VERSION 5.7 ;
  NOWIREEXTENSIONATPIN ON ;
  DIVIDERCHAR "/" ;
  BUSBITCHARS "[]" ;
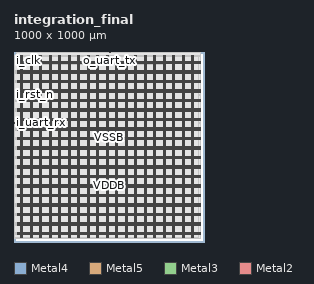
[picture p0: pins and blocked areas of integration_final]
MACRO integration_final
  CLASS BLOCK ;
  FOREIGN integration_final ;
  ORIGIN 0.000 0.000 ;
  SIZE 1000.000 BY 1000.000 ;
  PIN VDDB
    DIRECTION INOUT ;
    USE POWER ;
    PORT
      LAYER Metal4 ;
        RECT 42.080 23.220 43.680 980.300 ;
    END
    PORT
      LAYER Metal4 ;
        RECT 92.080 23.220 93.680 980.300 ;
    END
    PORT
      LAYER Metal4 ;
        RECT 142.080 23.220 143.680 980.300 ;
    END
    PORT
      LAYER Metal4 ;
        RECT 192.080 23.220 193.680 980.300 ;
    END
    PORT
      LAYER Metal4 ;
        RECT 242.080 23.220 243.680 980.300 ;
    END
    PORT
      LAYER Metal4 ;
        RECT 292.080 23.220 293.680 980.300 ;
    END
    PORT
      LAYER Metal4 ;
        RECT 342.080 23.220 343.680 980.300 ;
    END
    PORT
      LAYER Metal4 ;
        RECT 392.080 23.220 393.680 980.300 ;
    END
    PORT
      LAYER Metal4 ;
        RECT 442.080 23.220 443.680 980.300 ;
    END
    PORT
      LAYER Metal4 ;
        RECT 492.080 23.220 493.680 980.300 ;
    END
    PORT
      LAYER Metal4 ;
        RECT 542.080 23.220 543.680 980.300 ;
    END
    PORT
      LAYER Metal4 ;
        RECT 592.080 23.220 593.680 980.300 ;
    END
    PORT
      LAYER Metal4 ;
        RECT 642.080 23.220 643.680 980.300 ;
    END
    PORT
      LAYER Metal4 ;
        RECT 692.080 23.220 693.680 980.300 ;
    END
    PORT
      LAYER Metal4 ;
        RECT 742.080 23.220 743.680 980.300 ;
    END
    PORT
      LAYER Metal4 ;
        RECT 792.080 23.220 793.680 980.300 ;
    END
    PORT
      LAYER Metal4 ;
        RECT 842.080 23.220 843.680 980.300 ;
    END
    PORT
      LAYER Metal4 ;
        RECT 892.080 23.220 893.680 980.300 ;
    END
    PORT
      LAYER Metal4 ;
        RECT 942.080 23.220 943.680 980.300 ;
    END
    PORT
      LAYER Metal5 ;
        RECT 20.160 45.770 980.000 47.370 ;
    END
    PORT
      LAYER Metal5 ;
        RECT 20.160 95.770 980.000 97.370 ;
    END
    PORT
      LAYER Metal5 ;
        RECT 20.160 145.770 980.000 147.370 ;
    END
    PORT
      LAYER Metal5 ;
        RECT 20.160 195.770 980.000 197.370 ;
    END
    PORT
      LAYER Metal5 ;
        RECT 20.160 245.770 980.000 247.370 ;
    END
    PORT
      LAYER Metal5 ;
        RECT 20.160 295.770 980.000 297.370 ;
    END
    PORT
      LAYER Metal5 ;
        RECT 20.160 345.770 980.000 347.370 ;
    END
    PORT
      LAYER Metal5 ;
        RECT 20.160 395.770 980.000 397.370 ;
    END
    PORT
      LAYER Metal5 ;
        RECT 20.160 445.770 980.000 447.370 ;
    END
    PORT
      LAYER Metal5 ;
        RECT 20.160 495.770 980.000 497.370 ;
    END
    PORT
      LAYER Metal5 ;
        RECT 20.160 545.770 980.000 547.370 ;
    END
    PORT
      LAYER Metal5 ;
        RECT 20.160 595.770 980.000 597.370 ;
    END
    PORT
      LAYER Metal5 ;
        RECT 20.160 645.770 980.000 647.370 ;
    END
    PORT
      LAYER Metal5 ;
        RECT 20.160 695.770 980.000 697.370 ;
    END
    PORT
      LAYER Metal5 ;
        RECT 20.160 745.770 980.000 747.370 ;
    END
    PORT
      LAYER Metal5 ;
        RECT 20.160 795.770 980.000 797.370 ;
    END
    PORT
      LAYER Metal5 ;
        RECT 20.160 845.770 980.000 847.370 ;
    END
    PORT
      LAYER Metal5 ;
        RECT 20.160 895.770 980.000 897.370 ;
    END
    PORT
      LAYER Metal5 ;
        RECT 20.160 945.770 980.000 947.370 ;
    END
  END VDDB
  PIN VDDD
    DIRECTION INOUT ;
    USE POWER ;
    PORT
      LAYER Metal4 ;
        RECT 35.680 23.220 37.280 980.300 ;
    END
    PORT
      LAYER Metal4 ;
        RECT 85.680 23.220 87.280 980.300 ;
    END
    PORT
      LAYER Metal4 ;
        RECT 135.680 23.220 137.280 980.300 ;
    END
    PORT
      LAYER Metal4 ;
        RECT 185.680 23.220 187.280 980.300 ;
    END
    PORT
      LAYER Metal4 ;
        RECT 235.680 23.220 237.280 980.300 ;
    END
    PORT
      LAYER Metal4 ;
        RECT 285.680 23.220 287.280 980.300 ;
    END
    PORT
      LAYER Metal4 ;
        RECT 335.680 23.220 337.280 980.300 ;
    END
    PORT
      LAYER Metal4 ;
        RECT 385.680 23.220 387.280 980.300 ;
    END
    PORT
      LAYER Metal4 ;
        RECT 435.680 23.220 437.280 980.300 ;
    END
    PORT
      LAYER Metal4 ;
        RECT 485.680 23.220 487.280 980.300 ;
    END
    PORT
      LAYER Metal4 ;
        RECT 535.680 23.220 537.280 980.300 ;
    END
    PORT
      LAYER Metal4 ;
        RECT 585.680 23.220 587.280 980.300 ;
    END
    PORT
      LAYER Metal4 ;
        RECT 635.680 23.220 637.280 980.300 ;
    END
    PORT
      LAYER Metal4 ;
        RECT 685.680 23.220 687.280 980.300 ;
    END
    PORT
      LAYER Metal4 ;
        RECT 735.680 23.220 737.280 980.300 ;
    END
    PORT
      LAYER Metal4 ;
        RECT 785.680 23.220 787.280 980.300 ;
    END
    PORT
      LAYER Metal4 ;
        RECT 835.680 23.220 837.280 980.300 ;
    END
    PORT
      LAYER Metal4 ;
        RECT 885.680 23.220 887.280 980.300 ;
    END
    PORT
      LAYER Metal4 ;
        RECT 935.680 23.220 937.280 980.300 ;
    END
    PORT
      LAYER Metal5 ;
        RECT 20.160 39.370 980.000 40.970 ;
    END
    PORT
      LAYER Metal5 ;
        RECT 20.160 89.370 980.000 90.970 ;
    END
    PORT
      LAYER Metal5 ;
        RECT 20.160 139.370 980.000 140.970 ;
    END
    PORT
      LAYER Metal5 ;
        RECT 20.160 189.370 980.000 190.970 ;
    END
    PORT
      LAYER Metal5 ;
        RECT 20.160 239.370 980.000 240.970 ;
    END
    PORT
      LAYER Metal5 ;
        RECT 20.160 289.370 980.000 290.970 ;
    END
    PORT
      LAYER Metal5 ;
        RECT 20.160 339.370 980.000 340.970 ;
    END
    PORT
      LAYER Metal5 ;
        RECT 20.160 389.370 980.000 390.970 ;
    END
    PORT
      LAYER Metal5 ;
        RECT 20.160 439.370 980.000 440.970 ;
    END
    PORT
      LAYER Metal5 ;
        RECT 20.160 489.370 980.000 490.970 ;
    END
    PORT
      LAYER Metal5 ;
        RECT 20.160 539.370 980.000 540.970 ;
    END
    PORT
      LAYER Metal5 ;
        RECT 20.160 589.370 980.000 590.970 ;
    END
    PORT
      LAYER Metal5 ;
        RECT 20.160 639.370 980.000 640.970 ;
    END
    PORT
      LAYER Metal5 ;
        RECT 20.160 689.370 980.000 690.970 ;
    END
    PORT
      LAYER Metal5 ;
        RECT 20.160 739.370 980.000 740.970 ;
    END
    PORT
      LAYER Metal5 ;
        RECT 20.160 789.370 980.000 790.970 ;
    END
    PORT
      LAYER Metal5 ;
        RECT 20.160 839.370 980.000 840.970 ;
    END
    PORT
      LAYER Metal5 ;
        RECT 20.160 889.370 980.000 890.970 ;
    END
    PORT
      LAYER Metal5 ;
        RECT 20.160 939.370 980.000 940.970 ;
    END
  END VDDD
  PIN VSSB
    DIRECTION INOUT ;
    USE GROUND ;
    PORT
      LAYER Metal4 ;
        RECT 45.280 23.220 46.880 980.300 ;
    END
    PORT
      LAYER Metal4 ;
        RECT 95.280 23.220 96.880 980.300 ;
    END
    PORT
      LAYER Metal4 ;
        RECT 145.280 23.220 146.880 980.300 ;
    END
    PORT
      LAYER Metal4 ;
        RECT 195.280 23.220 196.880 980.300 ;
    END
    PORT
      LAYER Metal4 ;
        RECT 245.280 23.220 246.880 980.300 ;
    END
    PORT
      LAYER Metal4 ;
        RECT 295.280 23.220 296.880 980.300 ;
    END
    PORT
      LAYER Metal4 ;
        RECT 345.280 23.220 346.880 980.300 ;
    END
    PORT
      LAYER Metal4 ;
        RECT 395.280 23.220 396.880 980.300 ;
    END
    PORT
      LAYER Metal4 ;
        RECT 445.280 23.220 446.880 980.300 ;
    END
    PORT
      LAYER Metal4 ;
        RECT 495.280 23.220 496.880 980.300 ;
    END
    PORT
      LAYER Metal4 ;
        RECT 545.280 23.220 546.880 980.300 ;
    END
    PORT
      LAYER Metal4 ;
        RECT 595.280 23.220 596.880 980.300 ;
    END
    PORT
      LAYER Metal4 ;
        RECT 645.280 23.220 646.880 980.300 ;
    END
    PORT
      LAYER Metal4 ;
        RECT 695.280 23.220 696.880 980.300 ;
    END
    PORT
      LAYER Metal4 ;
        RECT 745.280 23.220 746.880 980.300 ;
    END
    PORT
      LAYER Metal4 ;
        RECT 795.280 23.220 796.880 980.300 ;
    END
    PORT
      LAYER Metal4 ;
        RECT 845.280 23.220 846.880 980.300 ;
    END
    PORT
      LAYER Metal4 ;
        RECT 895.280 23.220 896.880 980.300 ;
    END
    PORT
      LAYER Metal4 ;
        RECT 945.280 23.220 946.880 980.300 ;
    END
    PORT
      LAYER Metal5 ;
        RECT 20.160 48.970 980.000 50.570 ;
    END
    PORT
      LAYER Metal5 ;
        RECT 20.160 98.970 980.000 100.570 ;
    END
    PORT
      LAYER Metal5 ;
        RECT 20.160 148.970 980.000 150.570 ;
    END
    PORT
      LAYER Metal5 ;
        RECT 20.160 198.970 980.000 200.570 ;
    END
    PORT
      LAYER Metal5 ;
        RECT 20.160 248.970 980.000 250.570 ;
    END
    PORT
      LAYER Metal5 ;
        RECT 20.160 298.970 980.000 300.570 ;
    END
    PORT
      LAYER Metal5 ;
        RECT 20.160 348.970 980.000 350.570 ;
    END
    PORT
      LAYER Metal5 ;
        RECT 20.160 398.970 980.000 400.570 ;
    END
    PORT
      LAYER Metal5 ;
        RECT 20.160 448.970 980.000 450.570 ;
    END
    PORT
      LAYER Metal5 ;
        RECT 20.160 498.970 980.000 500.570 ;
    END
    PORT
      LAYER Metal5 ;
        RECT 20.160 548.970 980.000 550.570 ;
    END
    PORT
      LAYER Metal5 ;
        RECT 20.160 598.970 980.000 600.570 ;
    END
    PORT
      LAYER Metal5 ;
        RECT 20.160 648.970 980.000 650.570 ;
    END
    PORT
      LAYER Metal5 ;
        RECT 20.160 698.970 980.000 700.570 ;
    END
    PORT
      LAYER Metal5 ;
        RECT 20.160 748.970 980.000 750.570 ;
    END
    PORT
      LAYER Metal5 ;
        RECT 20.160 798.970 980.000 800.570 ;
    END
    PORT
      LAYER Metal5 ;
        RECT 20.160 848.970 980.000 850.570 ;
    END
    PORT
      LAYER Metal5 ;
        RECT 20.160 898.970 980.000 900.570 ;
    END
    PORT
      LAYER Metal5 ;
        RECT 20.160 948.970 980.000 950.570 ;
    END
  END VSSB
  PIN VSSD
    DIRECTION INOUT ;
    USE GROUND ;
    PORT
      LAYER Metal4 ;
        RECT 38.880 23.220 40.480 980.300 ;
    END
    PORT
      LAYER Metal4 ;
        RECT 88.880 23.220 90.480 980.300 ;
    END
    PORT
      LAYER Metal4 ;
        RECT 138.880 23.220 140.480 980.300 ;
    END
    PORT
      LAYER Metal4 ;
        RECT 188.880 23.220 190.480 980.300 ;
    END
    PORT
      LAYER Metal4 ;
        RECT 238.880 23.220 240.480 980.300 ;
    END
    PORT
      LAYER Metal4 ;
        RECT 288.880 23.220 290.480 980.300 ;
    END
    PORT
      LAYER Metal4 ;
        RECT 338.880 23.220 340.480 980.300 ;
    END
    PORT
      LAYER Metal4 ;
        RECT 388.880 23.220 390.480 980.300 ;
    END
    PORT
      LAYER Metal4 ;
        RECT 438.880 23.220 440.480 980.300 ;
    END
    PORT
      LAYER Metal4 ;
        RECT 488.880 23.220 490.480 980.300 ;
    END
    PORT
      LAYER Metal4 ;
        RECT 538.880 23.220 540.480 980.300 ;
    END
    PORT
      LAYER Metal4 ;
        RECT 588.880 23.220 590.480 980.300 ;
    END
    PORT
      LAYER Metal4 ;
        RECT 638.880 23.220 640.480 980.300 ;
    END
    PORT
      LAYER Metal4 ;
        RECT 688.880 23.220 690.480 980.300 ;
    END
    PORT
      LAYER Metal4 ;
        RECT 738.880 23.220 740.480 980.300 ;
    END
    PORT
      LAYER Metal4 ;
        RECT 788.880 23.220 790.480 980.300 ;
    END
    PORT
      LAYER Metal4 ;
        RECT 838.880 23.220 840.480 980.300 ;
    END
    PORT
      LAYER Metal4 ;
        RECT 888.880 23.220 890.480 980.300 ;
    END
    PORT
      LAYER Metal4 ;
        RECT 938.880 23.220 940.480 980.300 ;
    END
    PORT
      LAYER Metal5 ;
        RECT 20.160 42.570 980.000 44.170 ;
    END
    PORT
      LAYER Metal5 ;
        RECT 20.160 92.570 980.000 94.170 ;
    END
    PORT
      LAYER Metal5 ;
        RECT 20.160 142.570 980.000 144.170 ;
    END
    PORT
      LAYER Metal5 ;
        RECT 20.160 192.570 980.000 194.170 ;
    END
    PORT
      LAYER Metal5 ;
        RECT 20.160 242.570 980.000 244.170 ;
    END
    PORT
      LAYER Metal5 ;
        RECT 20.160 292.570 980.000 294.170 ;
    END
    PORT
      LAYER Metal5 ;
        RECT 20.160 342.570 980.000 344.170 ;
    END
    PORT
      LAYER Metal5 ;
        RECT 20.160 392.570 980.000 394.170 ;
    END
    PORT
      LAYER Metal5 ;
        RECT 20.160 442.570 980.000 444.170 ;
    END
    PORT
      LAYER Metal5 ;
        RECT 20.160 492.570 980.000 494.170 ;
    END
    PORT
      LAYER Metal5 ;
        RECT 20.160 542.570 980.000 544.170 ;
    END
    PORT
      LAYER Metal5 ;
        RECT 20.160 592.570 980.000 594.170 ;
    END
    PORT
      LAYER Metal5 ;
        RECT 20.160 642.570 980.000 644.170 ;
    END
    PORT
      LAYER Metal5 ;
        RECT 20.160 692.570 980.000 694.170 ;
    END
    PORT
      LAYER Metal5 ;
        RECT 20.160 742.570 980.000 744.170 ;
    END
    PORT
      LAYER Metal5 ;
        RECT 20.160 792.570 980.000 794.170 ;
    END
    PORT
      LAYER Metal5 ;
        RECT 20.160 842.570 980.000 844.170 ;
    END
    PORT
      LAYER Metal5 ;
        RECT 20.160 892.570 980.000 894.170 ;
    END
    PORT
      LAYER Metal5 ;
        RECT 20.160 942.570 980.000 944.170 ;
    END
  END VSSD
  PIN i_clk
    DIRECTION INPUT ;
    USE SIGNAL ;
    ANTENNAGATEAREA 4.738000 ;
    ANTENNADIFFAREA 0.410400 ;
    PORT
      LAYER Metal3 ;
        RECT 0.000 974.400 0.560 974.960 ;
    END
  END i_clk
  PIN i_rst_n
    DIRECTION INPUT ;
    USE SIGNAL ;
    ANTENNAGATEAREA 1.183000 ;
    ANTENNADIFFAREA 0.410400 ;
    PORT
      LAYER Metal3 ;
        RECT 0.000 773.920 0.560 774.480 ;
    END
  END i_rst_n
  PIN i_uart_rx
    DIRECTION INPUT ;
    USE SIGNAL ;
    ANTENNAGATEAREA 0.741000 ;
    ANTENNADIFFAREA 0.410400 ;
    PORT
      LAYER Metal3 ;
        RECT 0.000 626.080 0.560 626.640 ;
    END
  END i_uart_rx
  PIN o_uart_tx
    DIRECTION OUTPUT ;
    USE SIGNAL ;
    ANTENNADIFFAREA 0.897600 ;
    PORT
      LAYER Metal2 ;
        RECT 505.120 999.440 505.680 1000.000 ;
    END
  END o_uart_tx
  OBS
      LAYER Nwell ;
        RECT 19.730 23.090 980.430 980.430 ;
      LAYER Metal1 ;
        RECT 20.160 23.220 980.000 980.300 ;
      LAYER Metal2 ;
        RECT 15.260 999.140 504.820 999.440 ;
        RECT 505.980 999.140 979.300 999.440 ;
        RECT 15.260 19.690 979.300 999.140 ;
      LAYER Metal3 ;
        RECT 0.560 975.260 979.350 980.140 ;
        RECT 0.860 974.100 979.350 975.260 ;
        RECT 0.560 774.780 979.350 974.100 ;
        RECT 0.860 773.620 979.350 774.780 ;
        RECT 0.560 626.940 979.350 773.620 ;
        RECT 0.860 625.780 979.350 626.940 ;
        RECT 0.560 19.740 979.350 625.780 ;
      LAYER Metal4 ;
        RECT 5.180 25.290 35.380 973.750 ;
        RECT 37.580 25.290 38.580 973.750 ;
        RECT 40.780 25.290 41.780 973.750 ;
        RECT 43.980 25.290 44.980 973.750 ;
        RECT 47.180 25.290 85.380 973.750 ;
        RECT 87.580 25.290 88.580 973.750 ;
        RECT 90.780 25.290 91.780 973.750 ;
        RECT 93.980 25.290 94.980 973.750 ;
        RECT 97.180 25.290 135.380 973.750 ;
        RECT 137.580 25.290 138.580 973.750 ;
        RECT 140.780 25.290 141.780 973.750 ;
        RECT 143.980 25.290 144.980 973.750 ;
        RECT 147.180 25.290 185.380 973.750 ;
        RECT 187.580 25.290 188.580 973.750 ;
        RECT 190.780 25.290 191.780 973.750 ;
        RECT 193.980 25.290 194.980 973.750 ;
        RECT 197.180 25.290 235.380 973.750 ;
        RECT 237.580 25.290 238.580 973.750 ;
        RECT 240.780 25.290 241.780 973.750 ;
        RECT 243.980 25.290 244.980 973.750 ;
        RECT 247.180 25.290 285.380 973.750 ;
        RECT 287.580 25.290 288.580 973.750 ;
        RECT 290.780 25.290 291.780 973.750 ;
        RECT 293.980 25.290 294.980 973.750 ;
        RECT 297.180 25.290 335.380 973.750 ;
        RECT 337.580 25.290 338.580 973.750 ;
        RECT 340.780 25.290 341.780 973.750 ;
        RECT 343.980 25.290 344.980 973.750 ;
        RECT 347.180 25.290 385.380 973.750 ;
        RECT 387.580 25.290 388.580 973.750 ;
        RECT 390.780 25.290 391.780 973.750 ;
        RECT 393.980 25.290 394.980 973.750 ;
        RECT 397.180 25.290 435.380 973.750 ;
        RECT 437.580 25.290 438.580 973.750 ;
        RECT 440.780 25.290 441.780 973.750 ;
        RECT 443.980 25.290 444.980 973.750 ;
        RECT 447.180 25.290 485.380 973.750 ;
        RECT 487.580 25.290 488.580 973.750 ;
        RECT 490.780 25.290 491.780 973.750 ;
        RECT 493.980 25.290 494.980 973.750 ;
        RECT 497.180 25.290 535.380 973.750 ;
        RECT 537.580 25.290 538.580 973.750 ;
        RECT 540.780 25.290 541.780 973.750 ;
        RECT 543.980 25.290 544.980 973.750 ;
        RECT 547.180 25.290 585.380 973.750 ;
        RECT 587.580 25.290 588.580 973.750 ;
        RECT 590.780 25.290 591.780 973.750 ;
        RECT 593.980 25.290 594.980 973.750 ;
        RECT 597.180 25.290 635.380 973.750 ;
        RECT 637.580 25.290 638.580 973.750 ;
        RECT 640.780 25.290 641.780 973.750 ;
        RECT 643.980 25.290 644.980 973.750 ;
        RECT 647.180 25.290 685.380 973.750 ;
        RECT 687.580 25.290 688.580 973.750 ;
        RECT 690.780 25.290 691.780 973.750 ;
        RECT 693.980 25.290 694.980 973.750 ;
        RECT 697.180 25.290 735.380 973.750 ;
        RECT 737.580 25.290 738.580 973.750 ;
        RECT 740.780 25.290 741.780 973.750 ;
        RECT 743.980 25.290 744.980 973.750 ;
        RECT 747.180 25.290 785.380 973.750 ;
        RECT 787.580 25.290 788.580 973.750 ;
        RECT 790.780 25.290 791.780 973.750 ;
        RECT 793.980 25.290 794.980 973.750 ;
        RECT 797.180 25.290 835.380 973.750 ;
        RECT 837.580 25.290 838.580 973.750 ;
        RECT 840.780 25.290 841.780 973.750 ;
        RECT 843.980 25.290 844.980 973.750 ;
        RECT 847.180 25.290 885.380 973.750 ;
        RECT 887.580 25.290 888.580 973.750 ;
        RECT 890.780 25.290 891.780 973.750 ;
        RECT 893.980 25.290 894.980 973.750 ;
        RECT 897.180 25.290 935.380 973.750 ;
        RECT 937.580 25.290 938.580 973.750 ;
        RECT 940.780 25.290 941.780 973.750 ;
        RECT 943.980 25.290 944.980 973.750 ;
        RECT 947.180 25.290 972.020 973.750 ;
      LAYER Metal5 ;
        RECT 5.100 901.170 791.780 934.870 ;
        RECT 5.100 898.370 19.560 901.170 ;
        RECT 5.100 897.970 791.780 898.370 ;
        RECT 5.100 895.170 19.560 897.970 ;
        RECT 5.100 894.770 791.780 895.170 ;
        RECT 5.100 891.970 19.560 894.770 ;
        RECT 5.100 891.570 791.780 891.970 ;
        RECT 5.100 888.770 19.560 891.570 ;
        RECT 5.100 851.170 791.780 888.770 ;
        RECT 5.100 848.370 19.560 851.170 ;
        RECT 5.100 847.970 791.780 848.370 ;
        RECT 5.100 845.170 19.560 847.970 ;
        RECT 5.100 844.770 791.780 845.170 ;
        RECT 5.100 841.970 19.560 844.770 ;
        RECT 5.100 841.570 791.780 841.970 ;
        RECT 5.100 838.770 19.560 841.570 ;
        RECT 5.100 801.170 791.780 838.770 ;
        RECT 5.100 798.370 19.560 801.170 ;
        RECT 5.100 797.970 791.780 798.370 ;
        RECT 5.100 795.170 19.560 797.970 ;
        RECT 5.100 794.770 791.780 795.170 ;
        RECT 5.100 791.970 19.560 794.770 ;
        RECT 5.100 791.570 791.780 791.970 ;
        RECT 5.100 788.770 19.560 791.570 ;
        RECT 5.100 751.170 791.780 788.770 ;
        RECT 5.100 748.370 19.560 751.170 ;
        RECT 5.100 747.970 791.780 748.370 ;
        RECT 5.100 745.170 19.560 747.970 ;
        RECT 5.100 744.770 791.780 745.170 ;
        RECT 5.100 741.970 19.560 744.770 ;
        RECT 5.100 741.570 791.780 741.970 ;
        RECT 5.100 738.770 19.560 741.570 ;
        RECT 5.100 701.170 791.780 738.770 ;
        RECT 5.100 698.370 19.560 701.170 ;
        RECT 5.100 697.970 791.780 698.370 ;
        RECT 5.100 695.170 19.560 697.970 ;
        RECT 5.100 694.770 791.780 695.170 ;
        RECT 5.100 691.970 19.560 694.770 ;
        RECT 5.100 691.570 791.780 691.970 ;
        RECT 5.100 688.770 19.560 691.570 ;
        RECT 5.100 651.170 791.780 688.770 ;
        RECT 5.100 648.370 19.560 651.170 ;
        RECT 5.100 647.970 791.780 648.370 ;
        RECT 5.100 645.170 19.560 647.970 ;
        RECT 5.100 644.770 791.780 645.170 ;
        RECT 5.100 641.970 19.560 644.770 ;
        RECT 5.100 641.570 791.780 641.970 ;
        RECT 5.100 638.770 19.560 641.570 ;
        RECT 5.100 601.170 791.780 638.770 ;
        RECT 5.100 598.370 19.560 601.170 ;
        RECT 5.100 597.970 791.780 598.370 ;
        RECT 5.100 595.170 19.560 597.970 ;
        RECT 5.100 594.770 791.780 595.170 ;
        RECT 5.100 591.970 19.560 594.770 ;
        RECT 5.100 591.570 791.780 591.970 ;
        RECT 5.100 588.770 19.560 591.570 ;
        RECT 5.100 551.170 791.780 588.770 ;
        RECT 5.100 548.370 19.560 551.170 ;
        RECT 5.100 547.970 791.780 548.370 ;
        RECT 5.100 545.170 19.560 547.970 ;
        RECT 5.100 544.770 791.780 545.170 ;
        RECT 5.100 541.970 19.560 544.770 ;
        RECT 5.100 541.570 791.780 541.970 ;
        RECT 5.100 538.770 19.560 541.570 ;
        RECT 5.100 501.170 791.780 538.770 ;
        RECT 5.100 498.370 19.560 501.170 ;
        RECT 5.100 497.970 791.780 498.370 ;
        RECT 5.100 495.170 19.560 497.970 ;
        RECT 5.100 494.770 791.780 495.170 ;
        RECT 5.100 491.970 19.560 494.770 ;
        RECT 5.100 491.570 791.780 491.970 ;
        RECT 5.100 488.770 19.560 491.570 ;
        RECT 5.100 451.170 791.780 488.770 ;
        RECT 5.100 448.370 19.560 451.170 ;
        RECT 5.100 447.970 791.780 448.370 ;
        RECT 5.100 445.170 19.560 447.970 ;
        RECT 5.100 444.770 791.780 445.170 ;
        RECT 5.100 441.970 19.560 444.770 ;
        RECT 5.100 441.570 791.780 441.970 ;
        RECT 5.100 438.770 19.560 441.570 ;
        RECT 5.100 401.170 791.780 438.770 ;
        RECT 5.100 398.370 19.560 401.170 ;
        RECT 5.100 397.970 791.780 398.370 ;
        RECT 5.100 395.170 19.560 397.970 ;
        RECT 5.100 394.770 791.780 395.170 ;
        RECT 5.100 391.970 19.560 394.770 ;
        RECT 5.100 391.570 791.780 391.970 ;
        RECT 5.100 388.770 19.560 391.570 ;
        RECT 5.100 351.170 791.780 388.770 ;
        RECT 5.100 348.370 19.560 351.170 ;
        RECT 5.100 347.970 791.780 348.370 ;
        RECT 5.100 345.170 19.560 347.970 ;
        RECT 5.100 344.770 791.780 345.170 ;
        RECT 5.100 341.970 19.560 344.770 ;
        RECT 5.100 341.570 791.780 341.970 ;
        RECT 5.100 338.770 19.560 341.570 ;
        RECT 5.100 301.170 791.780 338.770 ;
        RECT 5.100 298.370 19.560 301.170 ;
        RECT 5.100 297.970 791.780 298.370 ;
        RECT 5.100 295.170 19.560 297.970 ;
        RECT 5.100 294.770 791.780 295.170 ;
        RECT 5.100 291.970 19.560 294.770 ;
        RECT 5.100 291.570 791.780 291.970 ;
        RECT 5.100 288.770 19.560 291.570 ;
        RECT 5.100 251.170 791.780 288.770 ;
        RECT 5.100 248.370 19.560 251.170 ;
        RECT 5.100 247.970 791.780 248.370 ;
        RECT 5.100 245.170 19.560 247.970 ;
        RECT 5.100 244.770 791.780 245.170 ;
        RECT 5.100 241.970 19.560 244.770 ;
        RECT 5.100 241.570 791.780 241.970 ;
        RECT 5.100 238.770 19.560 241.570 ;
        RECT 5.100 201.170 791.780 238.770 ;
        RECT 5.100 198.370 19.560 201.170 ;
        RECT 5.100 197.970 791.780 198.370 ;
        RECT 5.100 195.170 19.560 197.970 ;
        RECT 5.100 194.770 791.780 195.170 ;
        RECT 5.100 191.970 19.560 194.770 ;
        RECT 5.100 191.570 791.780 191.970 ;
        RECT 5.100 188.770 19.560 191.570 ;
        RECT 5.100 151.170 791.780 188.770 ;
        RECT 5.100 148.370 19.560 151.170 ;
        RECT 5.100 147.970 791.780 148.370 ;
        RECT 5.100 145.170 19.560 147.970 ;
        RECT 5.100 144.770 791.780 145.170 ;
        RECT 5.100 141.970 19.560 144.770 ;
        RECT 5.100 141.570 791.780 141.970 ;
        RECT 5.100 138.770 19.560 141.570 ;
        RECT 5.100 101.170 791.780 138.770 ;
        RECT 5.100 98.370 19.560 101.170 ;
        RECT 5.100 97.970 791.780 98.370 ;
        RECT 5.100 95.170 19.560 97.970 ;
        RECT 5.100 94.770 791.780 95.170 ;
        RECT 5.100 91.970 19.560 94.770 ;
        RECT 5.100 91.570 791.780 91.970 ;
        RECT 5.100 88.770 19.560 91.570 ;
        RECT 5.100 51.170 791.780 88.770 ;
        RECT 5.100 48.370 19.560 51.170 ;
        RECT 5.100 47.970 791.780 48.370 ;
        RECT 5.100 45.170 19.560 47.970 ;
        RECT 5.100 44.770 791.780 45.170 ;
        RECT 5.100 41.970 19.560 44.770 ;
        RECT 5.100 41.570 791.780 41.970 ;
        RECT 5.100 38.770 19.560 41.570 ;
        RECT 5.100 25.430 791.780 38.770 ;
  END
END integration_final
END LIBRARY

